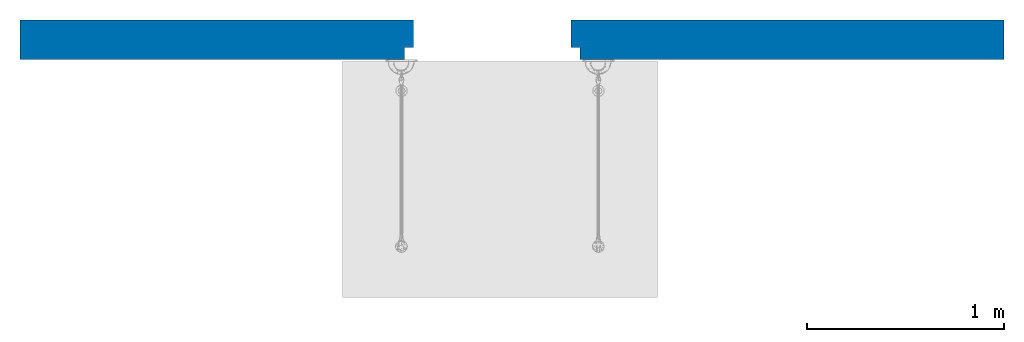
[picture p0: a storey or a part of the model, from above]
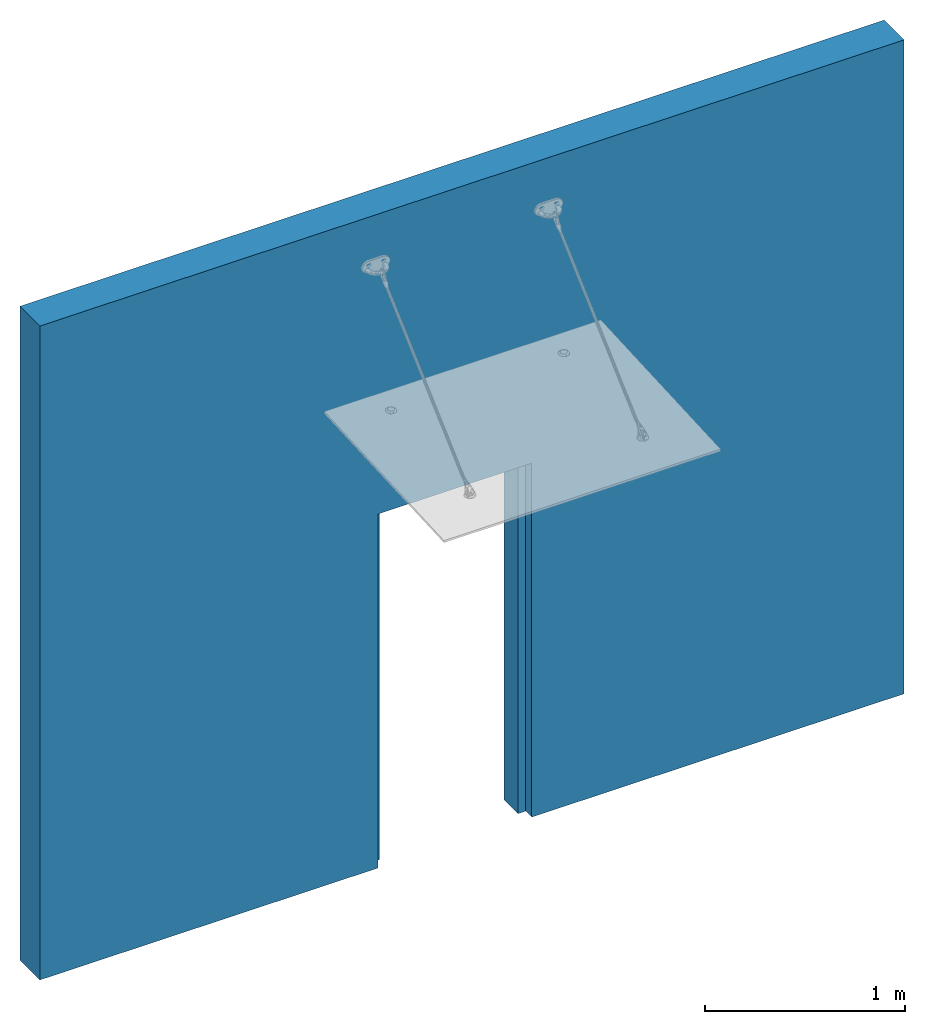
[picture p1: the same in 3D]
Properties of the parts of a building model (IFC4)

# File
Description: ViewDefinition [CoordinationView_V2.0, QuantityTakeOffAddOnView]
File name: REF_SFERA
Time: 2017-10-05T23:03:10
Written by: The EXPRESS Data Manager Version 5.02.0100.07 : 28 Aug 2013
Made in: 20150714_1515(x64) - Exporter 16.4.0.0 - Alternate UI 16.4.0.0
Comment: STEP Physical File produced by: The EXPRESS Data Manager Version 5.02.0100.07 : 28 Aug 2013 * Module: EDMstepFileFactory/EDMstandAlone * Creation date: Thu Oct 05 23:03:10 2017 * Host: AsusFede * Database: C:\Users\Federico\AppData\Local\Temp\{195774CE-444F-4466-BF68-656739325F3B}\ifc * Database version: 5507 * Database creation date: Thu Oct 05 23:03:08 2017 * Schema: IFC4 * Model: DataRepository.ifc * Model creation date: Thu Oct 05 23:03:09 2017 * Header model: DataRepository.ifc_HeaderModel * Header model creation date: Thu Oct 05 23:03:09 2017 * EDMuser: sdai-user * EDMgroup: sdai-group * License ID and type: 5605 : Permanent license. Expiry date: * EDMstepFileFactory options: 020000

# IfcProject, REF_SFERA
LongName: Sfera

# IfcSite, Default
RefLatitude: 42, 24, 53, 508911; RefLongitude: -71, -15, -29, -58837; RefElevation: 0 mm
Other - Category: Project Information; Project Issue Date: 21/08/17; Project Name: Sfera; Project Number: REF_SFERA

# IfcBuilding
Pset_BuildingCommon - Reference: Project Information; NumberOfStoreys: 1
Other - Category: Project Information; Project Issue Date: 21/08/17; Project Name: Sfera; Project Number: REF_SFERA

# IfcBuildingStorey, Livello 1
LongName: Livello 1; Elevation: 0 mm
Constraints - Elevation: 0 mm
Dimensions - Computation Height: 0 mm
Identity Data - Structural: no; Building Story: yes; Name: Livello 1
Other - Category: Levels; Family: Level: Livello 1; Family and Type: Level: Livello 1; Type: Level: Livello 1; Type Id: Level: Livello 1
Constraints(Type) - Elevation Base: Project Base Point
Graphics(Type) - Color: 0; Line Pattern: Solid; Line Weight: 1; Symbol at End 1 Default: no; Symbol at End 2 Default: yes
Identity Data(Type) - Type Name: Livello 1
Other(Type) - Category: Levels; Family Name: Level

# IfcOpeningElement: Opening, Basic Wall:Muro 1:2318
In: Livello 1
PredefinedType: OPENING

# IfcRailing: FAR_Can_GlassCanopies_Sfera_LOD300, FAR_Can_GlassCanopies_Sfera_LOD300:FAR_Can_GlassCanopies_Sfera_LOD300:2319
In: Livello 1
Type - Material: Alluminio 7075, Vetro, Vetratura trasparente, Temprato
Type - Dimensions(Type) - Glass_Max_Height: 1600 mm; Medium_Length: 1500 mm
Type - Graphics(Type) - Catalogue_Reference: Raster image: Catalogue_Reference.PNG; Fix_Point_Info_Img: Raster image: Registri.jpg; Image_Real: Raster image: REALE.jpg; Profile_Assembly: Raster image: Assembly.PNG
Type - Identity Data(Type) - Date of publishing: 21/08/2017; Design country: Italy; Manufacturer: Faraone srl - Architetture Trasparenti Via Po, 12 – 64018 Tortoreto Lido TE Tel. +39 0861 784200 – Fax +39 0861 781035 Partita IVA 00321830671 – faraone@faraone.it; Model: Sfera; Type Comments: SFERA. More care in design. Easier to mount. More substance for the Sfera-N model, which features a stainless steel AISI 316 steel structure with glossy finish. Glass 6 + 6 + 1.52 hardened and layered. Certified range up to 200 Kg / sqm; Type Name: FAR_Can_GlassCanopies_Sfera_LOD300; URL: http://faraone.it/; Version: 1.0; Video_Youtube: https://www.youtube.com/user/Faraonesrl
Type - Materials and Finishes(Type) - Material_Aluminium: Alluminio 6061; Material_Glass: Vetro, Vetratura trasparente, Temprato
Type - Other(Type) - Category: Railings; Family Name: FAR_Can_GlassCanopies_Sfera_LOD300; LED_Compatibility: no
Type - Structural Analysis(Type) - Load_Capacity: 2000
Type - Text(Type) - Glass_Max_Dimensions: Glass maximum dimensions are due to ultiple factor such as usage destination and site condition. Glass plates will have same dimensions along the canopy distribution.; Glass_Standard_Dimensions: 1600x1200, 1600x1500, 2000x1200, 2000x1500.; Plastic_Insert_Info: For more information please refer to catalogue FARAONE INFORMS 20; Standard_Kit: 5 > Number of production days after order confirmation GLASS INCLUDED for standard measures to prompt delivery GLASS EXCLUDED for non-standard measure PEN1.2-N 160 x120 cm 6+6+0.76 PVB PEN1.3-N 200 x120 cm 6+6+0.76 PVB PEN1.4-N 160 x150 cm 6+6+0.76 PVB PEN1.5-N 200 x150 cm 6+6+0.76 PVB PEN1-K 160/120 160x120 cm 6+6+0.76 PVB PEN1-K 200/120 200x120 cm 6+6+0.76 PVB PEN1-K 160/150 160x150 cm 6+6+0.76 PVB PEN1-K 200/150 200x150 cm 6+6+0.76 PVB. Fixing screws to be ordered separately Aluminium profiles are supplied already drilled and complete with accessories.
Pset_RailingCommon - IsExternal: yes; Reference: FAR_Can_GlassCanopies_Sfera_LOD300:FAR_Can_GlassCanopies_Sfera_LOD300
Pset_ManufacturerTypeInformation - Manufacturer: Faraone srl - Architetture Trasparenti Via Po, 12 – 64018 Tortoreto Lido TE Tel. +39 0861 784200 – Fax +39 0861 781035 Partita IVA 00321830671 – faraone@faraone.it
Constraints - Elevation: 2772.1 mm; Level: Level: Livello 1
Dimensions - Area: 2.13804 m2; Volume: 0.0274932 m3
Other - Category: Railings; Family: FAR_Can_GlassCanopies_Sfera_LOD300: FAR_Can_GlassCanopies_Sfera_LOD300; Family and Type: FAR_Can_GlassCanopies_Sfera_LOD300: FAR_Can_GlassCanopies_Sfera_LOD300; Host Id: Basic Wall: Muro 1; Type: FAR_Can_GlassCanopies_Sfera_LOD300: FAR_Can_GlassCanopies_Sfera_LOD300; Type Id: FAR_Can_GlassCanopies_Sfera_LOD300: FAR_Can_GlassCanopies_Sfera_LOD300
Phasing - Phase Created: Nuova costruzione

# IfcWallStandardCase: Basic Wall:Muro 1, Basic Wall:Muro 1:2318
In: Livello 1
Type - Material: Acciaio inossidabile 200 mm
Type - Analytical Properties(Type) - Absorptance: 0.1; Roughness: 1
Type - Construction(Type) - Function: Exterior; Width: 200 mm; Wrapping at Inserts: Do not wrap
Type - Graphics(Type) - Coarse Scale Fill Color: 0
Type - Identity Data(Type) - Type Name: Muro 1
Type - Other(Type) - Category: Walls; Family Name: Basic Wall
BaseQuantities - Height: 4000 mm; Length: 5000 mm; Width: 200 mm; GrossFootprintArea: 1 m2; GrossSideArea: 18.304 m2; GrossVolume: 3.64695 m3
Constraints - Base Constraint: Level: Livello 1; Base Extension Distance: 0 mm; Base is Attached: no; Base Offset: 0 mm; Location Line: Wall Centerline; Related to Mass: no; Room Bounding: yes; Top Extension Distance: 0 mm; Top is Attached: no; Top Offset: 0 mm; Unconnected Height: 4000 mm
Dimensions - Area: 18.304 m2; Length: 5000 mm; Volume: 3.64695 m3
Other - Category: Walls; Family: Basic Wall: Muro 1; Family and Type: Basic Wall: Muro 1; Type: Basic Wall: Muro 1; Type Id: Basic Wall: Muro 1
Phasing - Phase Created: Nuova costruzione
Structural - Enable Analytical Model: no; Structural: no; Structural Usage: Non-bearing
Pset_WallCommon - Reference: Basic Wall:Muro 1; LoadBearing: no; ExtendToStructure: no; IsExternal: yes
